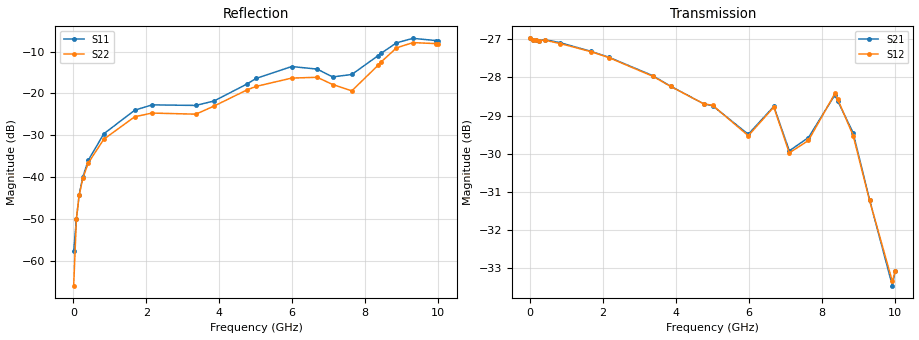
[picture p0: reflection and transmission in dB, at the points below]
! Device ID: PE43705
! Serial: 1
! Insertion: A
! Impedance: 50 ohm
! Temp: 25C
! VDD: 3.400V
! Attenuation Step: 26.00dB
#  Hz  S  RI  R  50
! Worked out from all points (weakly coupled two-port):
!   401 points, 10 MHz to 10.01 GHz, reference 50 ohm
!   highest |S21| = -26.98 dB at 10 MHz (marker M1); lowest = -33.5 dB at 9.935 GHz (marker M2)
!   lowest |S11| = -57.7 dB at 10 MHz (marker M3), VSWR 1.00, Z = 49.9 + j0.0438 ohm
!   |S11| at or under -10 dB: start of sweep to 8.492 GHz
!   |S22| runs from -65.8 to -7.8 dB; largest |S21 - S12| = 0.00072
!   S11 on the Smith chart (normalised r, x): 10 MHz: 1.00, +0.00; 4.76 GHz: 0.80, +0.12; 8.435 GHz: 0.80, +0.53; 9.31 GHz: 0.52, +0.55; 10.01 GHz: 0.47, +0.33
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1e7  -0.00123 0.000439  0.0448 -0.00015  0.0448 -0.000107  -0.000113 0.000498
8.5e7  -0.00104 0.00301  0.0446 -0.00103  0.0446 -0.00105  0.00048 0.00318
1.6e8  -0.00146 0.00599  0.0446 -0.00195  0.0446 -0.00191  0.000218 0.00609
2.6e8  -0.00277 0.00968  0.0444 -0.0031  0.0444 -0.00302  -0.000871 0.00971
4.1e8  -0.00595 0.0148  0.0444 -0.00456  0.0443 -0.00476  -0.00354 0.0144
8.35e8  -0.0237 0.023  0.0432 -0.00938  0.0431 -0.00932  -0.0183 0.0218
1.685e9  -0.0624 0.0102  0.0393 -0.0176  0.0393 -0.0175  -0.0515 0.0117
2.16e9  -0.073 -0.00438  0.0364 -0.0216  0.0364 -0.0215  -0.0584 0.000694
3.36e9  -0.0719 -0.00329  0.0274 -0.0292  0.0274 -0.0291  -0.0564 0.00491
3.86e9  -0.0785 0.0215  0.0234 -0.0309  0.0235 -0.0308  -0.0679 0.0201
4.76e9  -0.1058 0.0748  0.0172 -0.0325  0.0172 -0.0325  -0.0964 0.0532
5.01e9  -0.1213 0.0898  0.0157 -0.033  0.0158 -0.033  -0.1057 0.0597
5.985e9  -0.1756 0.1142  0.00864 -0.0324  0.00884 -0.0322  -0.132 0.0763
6.685e9  -0.1668 0.1015  0.00587 -0.036  0.00604 -0.0359  -0.1387 0.0712
7.11e9  -0.1318 0.0864  0.000205 -0.0319  0.00034 -0.0317  -0.1051 0.0729
7.635e9  -0.0829 0.1465  0.000548 -0.0332  0.00103 -0.0329  -0.0548 0.0924
8.36e9  -0.0229 0.2823  -0.00892 -0.0367  -0.00878 -0.0369  -0.0334 0.2153
8.435e9  -0.0249 0.2998  -0.0101 -0.0357  -0.0101 -0.0359  -0.036 0.234
8.86e9  -0.0754 0.3942  -0.0155 -0.0299  -0.0149 -0.0299  -0.0933 0.3371
9.31e9  -0.162 0.424  -0.0148 -0.0232  -0.0147 -0.0232  -0.1858 0.3585
9.935e9  -0.292 0.3127  -0.00551 -0.0205  -0.00545 -0.0208  -0.3298 0.2144
1.001e10  -0.2995 0.2898  -0.0045 -0.0217  -0.00448 -0.0217  -0.3438 0.1857
